VERSION 5.7 ;
  NOWIREEXTENSIONATPIN ON ;
  DIVIDERCHAR "/" ;
  BUSBITCHARS "[]" ;
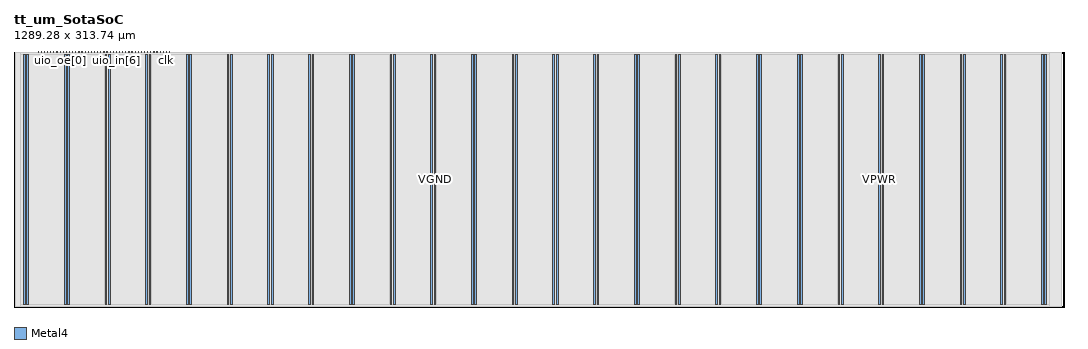
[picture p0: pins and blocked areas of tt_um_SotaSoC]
MACRO tt_um_SotaSoC
  CLASS BLOCK ;
  FOREIGN tt_um_SotaSoC ;
  ORIGIN 0.000 0.000 ;
  SIZE 1289.280 BY 313.740 ;
  PIN VGND
    DIRECTION INOUT ;
    USE GROUND ;
    PORT
      LAYER Metal4 ;
        RECT 15.930 3.560 18.030 310.180 ;
    END
    PORT
      LAYER Metal4 ;
        RECT 65.930 3.560 68.030 310.180 ;
    END
    PORT
      LAYER Metal4 ;
        RECT 115.930 3.560 118.030 310.180 ;
    END
    PORT
      LAYER Metal4 ;
        RECT 165.930 3.560 168.030 310.180 ;
    END
    PORT
      LAYER Metal4 ;
        RECT 215.930 3.560 218.030 310.180 ;
    END
    PORT
      LAYER Metal4 ;
        RECT 265.930 3.560 268.030 310.180 ;
    END
    PORT
      LAYER Metal4 ;
        RECT 315.930 3.560 318.030 310.180 ;
    END
    PORT
      LAYER Metal4 ;
        RECT 365.930 3.560 368.030 310.180 ;
    END
    PORT
      LAYER Metal4 ;
        RECT 415.930 3.560 418.030 310.180 ;
    END
    PORT
      LAYER Metal4 ;
        RECT 465.930 3.560 468.030 310.180 ;
    END
    PORT
      LAYER Metal4 ;
        RECT 515.930 3.560 518.030 310.180 ;
    END
    PORT
      LAYER Metal4 ;
        RECT 565.930 3.560 568.030 310.180 ;
    END
    PORT
      LAYER Metal4 ;
        RECT 615.930 3.560 618.030 310.180 ;
    END
    PORT
      LAYER Metal4 ;
        RECT 665.930 3.560 668.030 310.180 ;
    END
    PORT
      LAYER Metal4 ;
        RECT 715.930 3.560 718.030 310.180 ;
    END
    PORT
      LAYER Metal4 ;
        RECT 765.930 3.560 768.030 310.180 ;
    END
    PORT
      LAYER Metal4 ;
        RECT 815.930 3.560 818.030 310.180 ;
    END
    PORT
      LAYER Metal4 ;
        RECT 865.930 3.560 868.030 310.180 ;
    END
    PORT
      LAYER Metal4 ;
        RECT 915.930 3.560 918.030 310.180 ;
    END
    PORT
      LAYER Metal4 ;
        RECT 965.930 3.560 968.030 310.180 ;
    END
    PORT
      LAYER Metal4 ;
        RECT 1015.930 3.560 1018.030 310.180 ;
    END
    PORT
      LAYER Metal4 ;
        RECT 1065.930 3.560 1068.030 310.180 ;
    END
    PORT
      LAYER Metal4 ;
        RECT 1115.930 3.560 1118.030 310.180 ;
    END
    PORT
      LAYER Metal4 ;
        RECT 1165.930 3.560 1168.030 310.180 ;
    END
    PORT
      LAYER Metal4 ;
        RECT 1215.930 3.560 1218.030 310.180 ;
    END
    PORT
      LAYER Metal4 ;
        RECT 1265.930 3.560 1268.030 310.180 ;
    END
  END VGND
  PIN VPWR
    DIRECTION INOUT ;
    USE POWER ;
    PORT
      LAYER Metal4 ;
        RECT 11.830 3.560 13.930 310.180 ;
    END
    PORT
      LAYER Metal4 ;
        RECT 61.830 3.560 63.930 310.180 ;
    END
    PORT
      LAYER Metal4 ;
        RECT 111.830 3.560 113.930 310.180 ;
    END
    PORT
      LAYER Metal4 ;
        RECT 161.830 3.560 163.930 310.180 ;
    END
    PORT
      LAYER Metal4 ;
        RECT 211.830 3.560 213.930 310.180 ;
    END
    PORT
      LAYER Metal4 ;
        RECT 261.830 3.560 263.930 310.180 ;
    END
    PORT
      LAYER Metal4 ;
        RECT 311.830 3.560 313.930 310.180 ;
    END
    PORT
      LAYER Metal4 ;
        RECT 361.830 3.560 363.930 310.180 ;
    END
    PORT
      LAYER Metal4 ;
        RECT 411.830 3.560 413.930 310.180 ;
    END
    PORT
      LAYER Metal4 ;
        RECT 461.830 3.560 463.930 310.180 ;
    END
    PORT
      LAYER Metal4 ;
        RECT 511.830 3.560 513.930 310.180 ;
    END
    PORT
      LAYER Metal4 ;
        RECT 561.830 3.560 563.930 310.180 ;
    END
    PORT
      LAYER Metal4 ;
        RECT 611.830 3.560 613.930 310.180 ;
    END
    PORT
      LAYER Metal4 ;
        RECT 661.830 3.560 663.930 310.180 ;
    END
    PORT
      LAYER Metal4 ;
        RECT 711.830 3.560 713.930 310.180 ;
    END
    PORT
      LAYER Metal4 ;
        RECT 761.830 3.560 763.930 310.180 ;
    END
    PORT
      LAYER Metal4 ;
        RECT 811.830 3.560 813.930 310.180 ;
    END
    PORT
      LAYER Metal4 ;
        RECT 861.830 3.560 863.930 310.180 ;
    END
    PORT
      LAYER Metal4 ;
        RECT 911.830 3.560 913.930 310.180 ;
    END
    PORT
      LAYER Metal4 ;
        RECT 961.830 3.560 963.930 310.180 ;
    END
    PORT
      LAYER Metal4 ;
        RECT 1011.830 3.560 1013.930 310.180 ;
    END
    PORT
      LAYER Metal4 ;
        RECT 1061.830 3.560 1063.930 310.180 ;
    END
    PORT
      LAYER Metal4 ;
        RECT 1111.830 3.560 1113.930 310.180 ;
    END
    PORT
      LAYER Metal4 ;
        RECT 1161.830 3.560 1163.930 310.180 ;
    END
    PORT
      LAYER Metal4 ;
        RECT 1211.830 3.560 1213.930 310.180 ;
    END
    PORT
      LAYER Metal4 ;
        RECT 1261.830 3.560 1263.930 310.180 ;
    END
  END VPWR
  PIN clk
    DIRECTION INPUT ;
    USE SIGNAL ;
    ANTENNAGATEAREA 0.725400 ;
    PORT
      LAYER Metal4 ;
        RECT 187.050 312.740 187.350 313.740 ;
    END
  END clk
  PIN ena
    DIRECTION INPUT ;
    USE SIGNAL ;
    PORT
      LAYER Metal4 ;
        RECT 190.890 312.740 191.190 313.740 ;
    END
  END ena
  PIN rst_n
    DIRECTION INPUT ;
    USE SIGNAL ;
    ANTENNAGATEAREA 0.180700 ;
    PORT
      LAYER Metal4 ;
        RECT 183.210 312.740 183.510 313.740 ;
    END
  END rst_n
  PIN ui_in[0]
    DIRECTION INPUT ;
    USE SIGNAL ;
    ANTENNAGATEAREA 0.180700 ;
    PORT
      LAYER Metal4 ;
        RECT 179.370 312.740 179.670 313.740 ;
    END
  END ui_in[0]
  PIN ui_in[1]
    DIRECTION INPUT ;
    USE SIGNAL ;
    ANTENNAGATEAREA 0.180700 ;
    PORT
      LAYER Metal4 ;
        RECT 175.530 312.740 175.830 313.740 ;
    END
  END ui_in[1]
  PIN ui_in[2]
    DIRECTION INPUT ;
    USE SIGNAL ;
    ANTENNAGATEAREA 0.180700 ;
    PORT
      LAYER Metal4 ;
        RECT 171.690 312.740 171.990 313.740 ;
    END
  END ui_in[2]
  PIN ui_in[3]
    DIRECTION INPUT ;
    USE SIGNAL ;
    ANTENNAGATEAREA 0.180700 ;
    PORT
      LAYER Metal4 ;
        RECT 167.850 312.740 168.150 313.740 ;
    END
  END ui_in[3]
  PIN ui_in[4]
    DIRECTION INPUT ;
    USE SIGNAL ;
    ANTENNAGATEAREA 0.180700 ;
    PORT
      LAYER Metal4 ;
        RECT 164.010 312.740 164.310 313.740 ;
    END
  END ui_in[4]
  PIN ui_in[5]
    DIRECTION INPUT ;
    USE SIGNAL ;
    ANTENNAGATEAREA 0.180700 ;
    PORT
      LAYER Metal4 ;
        RECT 160.170 312.740 160.470 313.740 ;
    END
  END ui_in[5]
  PIN ui_in[6]
    DIRECTION INPUT ;
    USE SIGNAL ;
    ANTENNAGATEAREA 0.180700 ;
    PORT
      LAYER Metal4 ;
        RECT 156.330 312.740 156.630 313.740 ;
    END
  END ui_in[6]
  PIN ui_in[7]
    DIRECTION INPUT ;
    USE SIGNAL ;
    ANTENNAGATEAREA 0.180700 ;
    PORT
      LAYER Metal4 ;
        RECT 152.490 312.740 152.790 313.740 ;
    END
  END ui_in[7]
  PIN uio_in[0]
    DIRECTION INPUT ;
    USE SIGNAL ;
    PORT
      LAYER Metal4 ;
        RECT 148.650 312.740 148.950 313.740 ;
    END
  END uio_in[0]
  PIN uio_in[1]
    DIRECTION INPUT ;
    USE SIGNAL ;
    ANTENNAGATEAREA 0.180700 ;
    PORT
      LAYER Metal4 ;
        RECT 144.810 312.740 145.110 313.740 ;
    END
  END uio_in[1]
  PIN uio_in[2]
    DIRECTION INPUT ;
    USE SIGNAL ;
    ANTENNAGATEAREA 0.180700 ;
    PORT
      LAYER Metal4 ;
        RECT 140.970 312.740 141.270 313.740 ;
    END
  END uio_in[2]
  PIN uio_in[3]
    DIRECTION INPUT ;
    USE SIGNAL ;
    PORT
      LAYER Metal4 ;
        RECT 137.130 312.740 137.430 313.740 ;
    END
  END uio_in[3]
  PIN uio_in[4]
    DIRECTION INPUT ;
    USE SIGNAL ;
    ANTENNAGATEAREA 0.180700 ;
    PORT
      LAYER Metal4 ;
        RECT 133.290 312.740 133.590 313.740 ;
    END
  END uio_in[4]
  PIN uio_in[5]
    DIRECTION INPUT ;
    USE SIGNAL ;
    ANTENNAGATEAREA 0.180700 ;
    PORT
      LAYER Metal4 ;
        RECT 129.450 312.740 129.750 313.740 ;
    END
  END uio_in[5]
  PIN uio_in[6]
    DIRECTION INPUT ;
    USE SIGNAL ;
    PORT
      LAYER Metal4 ;
        RECT 125.610 312.740 125.910 313.740 ;
    END
  END uio_in[6]
  PIN uio_in[7]
    DIRECTION INPUT ;
    USE SIGNAL ;
    ANTENNAGATEAREA 0.180700 ;
    PORT
      LAYER Metal4 ;
        RECT 121.770 312.740 122.070 313.740 ;
    END
  END uio_in[7]
  PIN uio_oe[0]
    DIRECTION OUTPUT ;
    USE SIGNAL ;
    ANTENNADIFFAREA 0.392700 ;
    PORT
      LAYER Metal4 ;
        RECT 56.490 312.740 56.790 313.740 ;
    END
  END uio_oe[0]
  PIN uio_oe[1]
    DIRECTION OUTPUT ;
    USE SIGNAL ;
    ANTENNADIFFAREA 0.708600 ;
    PORT
      LAYER Metal4 ;
        RECT 52.650 312.740 52.950 313.740 ;
    END
  END uio_oe[1]
  PIN uio_oe[2]
    DIRECTION OUTPUT ;
    USE SIGNAL ;
    ANTENNADIFFAREA 0.708600 ;
    PORT
      LAYER Metal4 ;
        RECT 48.810 312.740 49.110 313.740 ;
    END
  END uio_oe[2]
  PIN uio_oe[3]
    DIRECTION OUTPUT ;
    USE SIGNAL ;
    ANTENNADIFFAREA 0.392700 ;
    PORT
      LAYER Metal4 ;
        RECT 44.970 312.740 45.270 313.740 ;
    END
  END uio_oe[3]
  PIN uio_oe[4]
    DIRECTION OUTPUT ;
    USE SIGNAL ;
    ANTENNADIFFAREA 0.708600 ;
    PORT
      LAYER Metal4 ;
        RECT 41.130 312.740 41.430 313.740 ;
    END
  END uio_oe[4]
  PIN uio_oe[5]
    DIRECTION OUTPUT ;
    USE SIGNAL ;
    ANTENNAGATEAREA 0.651300 ;
    ANTENNADIFFAREA 0.632400 ;
    PORT
      LAYER Metal4 ;
        RECT 37.290 312.740 37.590 313.740 ;
    END
  END uio_oe[5]
  PIN uio_oe[6]
    DIRECTION OUTPUT ;
    USE SIGNAL ;
    ANTENNADIFFAREA 0.392700 ;
    PORT
      LAYER Metal4 ;
        RECT 33.450 312.740 33.750 313.740 ;
    END
  END uio_oe[6]
  PIN uio_oe[7]
    DIRECTION OUTPUT ;
    USE SIGNAL ;
    ANTENNADIFFAREA 1.008100 ;
    PORT
      LAYER Metal4 ;
        RECT 29.610 312.740 29.910 313.740 ;
    END
  END uio_oe[7]
  PIN uio_out[0]
    DIRECTION OUTPUT ;
    USE SIGNAL ;
    ANTENNADIFFAREA 0.708600 ;
    PORT
      LAYER Metal4 ;
        RECT 87.210 312.740 87.510 313.740 ;
    END
  END uio_out[0]
  PIN uio_out[1]
    DIRECTION OUTPUT ;
    USE SIGNAL ;
    ANTENNAGATEAREA 0.109200 ;
    ANTENNADIFFAREA 0.632400 ;
    PORT
      LAYER Metal4 ;
        RECT 83.370 312.740 83.670 313.740 ;
    END
  END uio_out[1]
  PIN uio_out[2]
    DIRECTION OUTPUT ;
    USE SIGNAL ;
    ANTENNAGATEAREA 0.351000 ;
    ANTENNADIFFAREA 0.632400 ;
    PORT
      LAYER Metal4 ;
        RECT 79.530 312.740 79.830 313.740 ;
    END
  END uio_out[2]
  PIN uio_out[3]
    DIRECTION OUTPUT ;
    USE SIGNAL ;
    ANTENNADIFFAREA 0.708600 ;
    PORT
      LAYER Metal4 ;
        RECT 75.690 312.740 75.990 313.740 ;
    END
  END uio_out[3]
  PIN uio_out[4]
    DIRECTION OUTPUT ;
    USE SIGNAL ;
    ANTENNAGATEAREA 0.109200 ;
    ANTENNADIFFAREA 0.632400 ;
    PORT
      LAYER Metal4 ;
        RECT 71.850 312.740 72.150 313.740 ;
    END
  END uio_out[4]
  PIN uio_out[5]
    DIRECTION OUTPUT ;
    USE SIGNAL ;
    ANTENNAGATEAREA 0.289900 ;
    ANTENNADIFFAREA 0.632400 ;
    PORT
      LAYER Metal4 ;
        RECT 68.010 312.740 68.310 313.740 ;
    END
  END uio_out[5]
  PIN uio_out[6]
    DIRECTION OUTPUT ;
    USE SIGNAL ;
    ANTENNADIFFAREA 0.708600 ;
    PORT
      LAYER Metal4 ;
        RECT 64.170 312.740 64.470 313.740 ;
    END
  END uio_out[6]
  PIN uio_out[7]
    DIRECTION OUTPUT ;
    USE SIGNAL ;
    ANTENNADIFFAREA 0.632400 ;
    PORT
      LAYER Metal4 ;
        RECT 60.330 312.740 60.630 313.740 ;
    END
  END uio_out[7]
  PIN uo_out[0]
    DIRECTION OUTPUT ;
    USE SIGNAL ;
    ANTENNADIFFAREA 0.708600 ;
    PORT
      LAYER Metal4 ;
        RECT 117.930 312.740 118.230 313.740 ;
    END
  END uo_out[0]
  PIN uo_out[1]
    DIRECTION OUTPUT ;
    USE SIGNAL ;
    ANTENNADIFFAREA 0.708600 ;
    PORT
      LAYER Metal4 ;
        RECT 114.090 312.740 114.390 313.740 ;
    END
  END uo_out[1]
  PIN uo_out[2]
    DIRECTION OUTPUT ;
    USE SIGNAL ;
    ANTENNADIFFAREA 0.677200 ;
    PORT
      LAYER Metal4 ;
        RECT 110.250 312.740 110.550 313.740 ;
    END
  END uo_out[2]
  PIN uo_out[3]
    DIRECTION OUTPUT ;
    USE SIGNAL ;
    ANTENNADIFFAREA 0.708600 ;
    PORT
      LAYER Metal4 ;
        RECT 106.410 312.740 106.710 313.740 ;
    END
  END uo_out[3]
  PIN uo_out[4]
    DIRECTION OUTPUT ;
    USE SIGNAL ;
    ANTENNADIFFAREA 1.008100 ;
    PORT
      LAYER Metal4 ;
        RECT 102.570 312.740 102.870 313.740 ;
    END
  END uo_out[4]
  PIN uo_out[5]
    DIRECTION OUTPUT ;
    USE SIGNAL ;
    ANTENNADIFFAREA 1.008100 ;
    PORT
      LAYER Metal4 ;
        RECT 98.730 312.740 99.030 313.740 ;
    END
  END uo_out[5]
  PIN uo_out[6]
    DIRECTION OUTPUT ;
    USE SIGNAL ;
    ANTENNADIFFAREA 0.677200 ;
    PORT
      LAYER Metal4 ;
        RECT 94.890 312.740 95.190 313.740 ;
    END
  END uo_out[6]
  PIN uo_out[7]
    DIRECTION OUTPUT ;
    USE SIGNAL ;
    ANTENNADIFFAREA 0.708600 ;
    PORT
      LAYER Metal4 ;
        RECT 91.050 312.740 91.350 313.740 ;
    END
  END uo_out[7]
  OBS
      LAYER GatPoly ;
        RECT 2.880 3.630 1286.400 310.110 ;
      LAYER Metal1 ;
        RECT 2.880 3.560 1286.400 310.180 ;
      LAYER Metal2 ;
        RECT 1.815 0.275 1286.025 313.045 ;
      LAYER Metal3 ;
        RECT 1.775 0.320 1286.065 313.005 ;
      LAYER Metal4 ;
        RECT 8.060 312.530 29.400 313.045 ;
        RECT 30.120 312.530 33.240 313.045 ;
        RECT 33.960 312.530 37.080 313.045 ;
        RECT 37.800 312.530 40.920 313.045 ;
        RECT 41.640 312.530 44.760 313.045 ;
        RECT 45.480 312.530 48.600 313.045 ;
        RECT 49.320 312.530 52.440 313.045 ;
        RECT 53.160 312.530 56.280 313.045 ;
        RECT 57.000 312.530 60.120 313.045 ;
        RECT 60.840 312.530 63.960 313.045 ;
        RECT 64.680 312.530 67.800 313.045 ;
        RECT 68.520 312.530 71.640 313.045 ;
        RECT 72.360 312.530 75.480 313.045 ;
        RECT 76.200 312.530 79.320 313.045 ;
        RECT 80.040 312.530 83.160 313.045 ;
        RECT 83.880 312.530 87.000 313.045 ;
        RECT 87.720 312.530 90.840 313.045 ;
        RECT 91.560 312.530 94.680 313.045 ;
        RECT 95.400 312.530 98.520 313.045 ;
        RECT 99.240 312.530 102.360 313.045 ;
        RECT 103.080 312.530 106.200 313.045 ;
        RECT 106.920 312.530 110.040 313.045 ;
        RECT 110.760 312.530 113.880 313.045 ;
        RECT 114.600 312.530 117.720 313.045 ;
        RECT 118.440 312.530 121.560 313.045 ;
        RECT 122.280 312.530 125.400 313.045 ;
        RECT 126.120 312.530 129.240 313.045 ;
        RECT 129.960 312.530 133.080 313.045 ;
        RECT 133.800 312.530 136.920 313.045 ;
        RECT 137.640 312.530 140.760 313.045 ;
        RECT 141.480 312.530 144.600 313.045 ;
        RECT 145.320 312.530 148.440 313.045 ;
        RECT 149.160 312.530 152.280 313.045 ;
        RECT 153.000 312.530 156.120 313.045 ;
        RECT 156.840 312.530 159.960 313.045 ;
        RECT 160.680 312.530 163.800 313.045 ;
        RECT 164.520 312.530 167.640 313.045 ;
        RECT 168.360 312.530 171.480 313.045 ;
        RECT 172.200 312.530 175.320 313.045 ;
        RECT 176.040 312.530 179.160 313.045 ;
        RECT 179.880 312.530 183.000 313.045 ;
        RECT 183.720 312.530 186.840 313.045 ;
        RECT 187.560 312.530 190.680 313.045 ;
        RECT 191.400 312.530 1271.140 313.045 ;
        RECT 8.060 310.390 1271.140 312.530 ;
        RECT 8.060 3.350 11.620 310.390 ;
        RECT 14.140 3.350 15.720 310.390 ;
        RECT 18.240 3.350 61.620 310.390 ;
        RECT 64.140 3.350 65.720 310.390 ;
        RECT 68.240 3.350 111.620 310.390 ;
        RECT 114.140 3.350 115.720 310.390 ;
        RECT 118.240 3.350 161.620 310.390 ;
        RECT 164.140 3.350 165.720 310.390 ;
        RECT 168.240 3.350 211.620 310.390 ;
        RECT 214.140 3.350 215.720 310.390 ;
        RECT 218.240 3.350 261.620 310.390 ;
        RECT 264.140 3.350 265.720 310.390 ;
        RECT 268.240 3.350 311.620 310.390 ;
        RECT 314.140 3.350 315.720 310.390 ;
        RECT 318.240 3.350 361.620 310.390 ;
        RECT 364.140 3.350 365.720 310.390 ;
        RECT 368.240 3.350 411.620 310.390 ;
        RECT 414.140 3.350 415.720 310.390 ;
        RECT 418.240 3.350 461.620 310.390 ;
        RECT 464.140 3.350 465.720 310.390 ;
        RECT 468.240 3.350 511.620 310.390 ;
        RECT 514.140 3.350 515.720 310.390 ;
        RECT 518.240 3.350 561.620 310.390 ;
        RECT 564.140 3.350 565.720 310.390 ;
        RECT 568.240 3.350 611.620 310.390 ;
        RECT 614.140 3.350 615.720 310.390 ;
        RECT 618.240 3.350 661.620 310.390 ;
        RECT 664.140 3.350 665.720 310.390 ;
        RECT 668.240 3.350 711.620 310.390 ;
        RECT 714.140 3.350 715.720 310.390 ;
        RECT 718.240 3.350 761.620 310.390 ;
        RECT 764.140 3.350 765.720 310.390 ;
        RECT 768.240 3.350 811.620 310.390 ;
        RECT 814.140 3.350 815.720 310.390 ;
        RECT 818.240 3.350 861.620 310.390 ;
        RECT 864.140 3.350 865.720 310.390 ;
        RECT 868.240 3.350 911.620 310.390 ;
        RECT 914.140 3.350 915.720 310.390 ;
        RECT 918.240 3.350 961.620 310.390 ;
        RECT 964.140 3.350 965.720 310.390 ;
        RECT 968.240 3.350 1011.620 310.390 ;
        RECT 1014.140 3.350 1015.720 310.390 ;
        RECT 1018.240 3.350 1061.620 310.390 ;
        RECT 1064.140 3.350 1065.720 310.390 ;
        RECT 1068.240 3.350 1111.620 310.390 ;
        RECT 1114.140 3.350 1115.720 310.390 ;
        RECT 1118.240 3.350 1161.620 310.390 ;
        RECT 1164.140 3.350 1165.720 310.390 ;
        RECT 1168.240 3.350 1211.620 310.390 ;
        RECT 1214.140 3.350 1215.720 310.390 ;
        RECT 1218.240 3.350 1261.620 310.390 ;
        RECT 1264.140 3.350 1265.720 310.390 ;
        RECT 1268.240 3.350 1271.140 310.390 ;
        RECT 8.060 0.695 1271.140 3.350 ;
  END
END tt_um_SotaSoC
END LIBRARY

